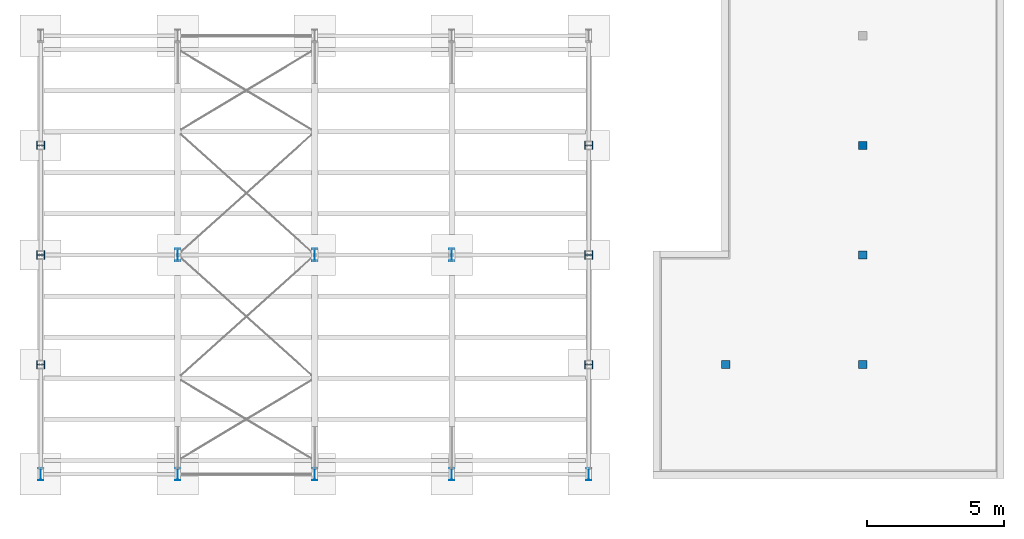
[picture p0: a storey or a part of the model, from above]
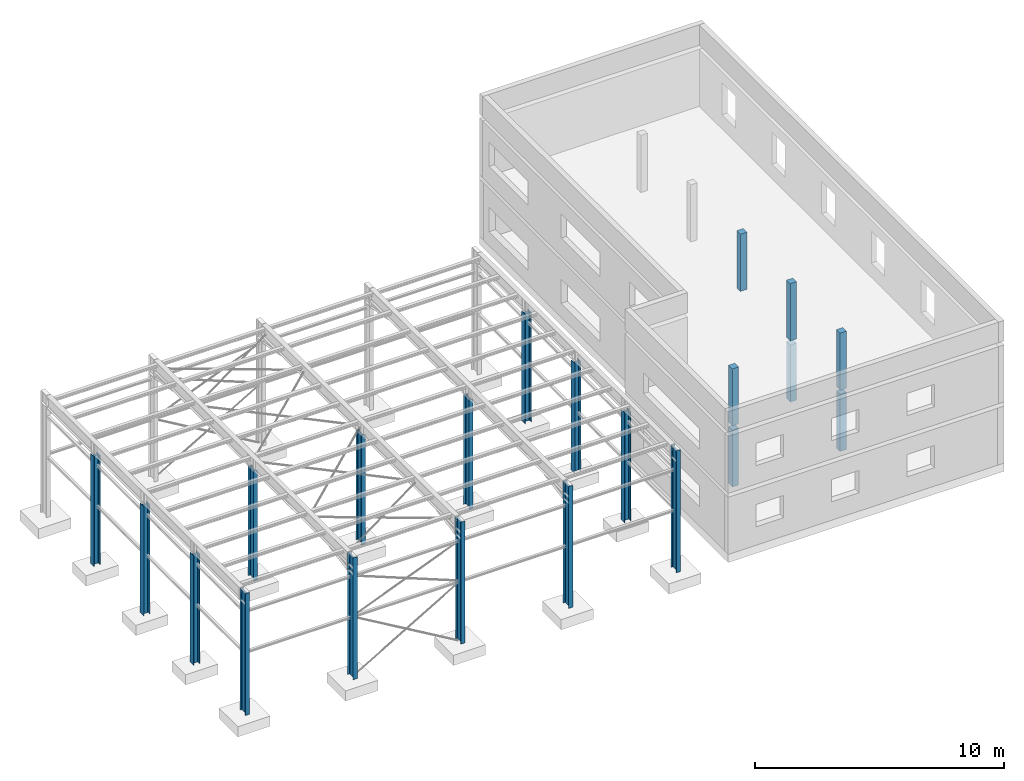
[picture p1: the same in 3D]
Properties of the parts of a building model (IFC4)

# File
Description: ViewDefinition [ReferenceView_V1.2], RevitIdentifiers [VersionGUID: 3cd32a00-ee76-47b4-9a76-ae202fe3ce4a, NumberOfSaves: 37], CoordinateReference [CoordinateBase: Gemeinsam genutzte Koordinaten], ExchangeRequirement [Structural]
File name: IFC_Vorführungsmodell_2.ifc
Time: 2025-12-05T14:43:31+01:00
Written by: ODA SDAI 24.11
Made in: Autodesk Revit 25.0.2.419 (DEU) - IFC 25.0.2.419

# IfcProject, 2018_01
Phase: Projekt Status

# IfcSite, Default
RefLatitude: 48, 8, 15, 359802; RefLongitude: 11, 34, 47, 783432; RefElevation: 0 m
Pset_SiteCommon - Reference: Projektinformationen

# IfcBeam: HEA Träger:HEA 120 (32)
In: Default
Type - PredefinedType: BEAM; Material: Metall - Baustahl S235
Type - Pset_BeamCommon - IsExternal: no; LoadBearing: yes
Pset_BeamCommon - Reference: HEA 120; Slope: 0 deg; Roll: 0 deg
Pset_EnvironmentalImpactIndicators - Reference: HEA 120; sets with these values: 2
Qto_BeamBaseQuantities - CrossSectionArea: 0.00253369 m2
Name (HEA Träger:HEA 120:...) | Span (m) | Length (m) | OuterSurfaceArea (m2) | GrossSurfaceArea (m2) = NetSurfaceArea (m2) | GrossVolume (m3) | NetVolume (m3)
2526143 | 5 | 4.7846 | 3.24108 | 3.24615 | 0.0121227 | 0.0121224
2526321 | 5 | 4.7846 | 3.24108 | 3.24615 | 0.0121227 | 0.0121224
2526471 | 5 | 4.7846 | 3.24108 | 3.24615 | 0.0121227 | 0.0121224
2526497 | 5 | 4.7846 | 3.24108 | 3.24615 | 0.0121227 | 0.0121224
2526596 | 4 | 3.5996 | 2.43836 | 2.44343 | 0.00912027 | 0.00912005
2526643 | 4 | 3.6746 | 2.48917 | 2.49423 | 0.0093103 | 0.00931007
2526716 | 4 | 3.6746 | 2.48917 | 2.49423 | 0.0093103 | 0.00931007
2526732 | 4 | 3.5996 | 2.43836 | 2.44343 | 0.00912027 | 0.00912005
2526779 | 5 | 4.7846 | 3.24108 | 3.24615 | 0.0121227 | 0.0121224
2526805 | 5 | 4.7846 | 3.24108 | 3.24615 | 0.0121227 | 0.0121224
2526849 | 5 | 4.7846 | 3.24108 | 3.24615 | 0.0121227 | 0.0121224
2526873 | 5 | 4.7846 | 3.24108 | 3.24615 | 0.0121227 | 0.0121224
2526911 | 4 | 3.5996 | 2.43836 | 2.44343 | 0.00912027 | 0.00912005
2526929 | 4 | 3.6746 | 2.48917 | 2.49423 | 0.0093103 | 0.00931007
2526979 | 4 | 3.6746 | 2.48917 | 2.49423 | 0.0093103 | 0.00931007
2527025 | 4 | 3.5996 | 2.43836 | 2.44343 | 0.00912027 | 0.00912005
2527203 | 5 | 4.7846 | 3.24108 | 3.24615 | 0.0121227 | 0.0121224
2527204 | 5 | 4.7846 | 3.24108 | 3.24615 | 0.0121227 | 0.0121224
2527205 | 5 | 4.7846 | 3.24108 | 3.24615 | 0.0121227 | 0.0121224
2527206 | 5 | 4.7846 | 3.24108 | 3.24615 | 0.0121227 | 0.0121224
2527208 | 4 | 3.6746 | 2.48917 | 2.49423 | 0.0093103 | 0.00931007
2527209 | 4 | 3.6746 | 2.48917 | 2.49423 | 0.0093103 | 0.00931007
2527210 | 4 | 3.5996 | 2.43836 | 2.44343 | 0.00912027 | 0.00912005
2527211 | 5 | 4.7846 | 3.24108 | 3.24615 | 0.0121227 | 0.0121224
2527212 | 5 | 4.7846 | 3.24108 | 3.24615 | 0.0121227 | 0.0121224
2527213 | 5 | 4.7846 | 3.24108 | 3.24615 | 0.0121227 | 0.0121224
2527214 | 5 | 4.7846 | 3.24108 | 3.24615 | 0.0121227 | 0.0121224
2527215 | 4 | 3.5996 | 2.43836 | 2.44343 | 0.00912027 | 0.00912005
2527216 | 4 | 3.6746 | 2.48917 | 2.49423 | 0.0093103 | 0.00931007
2527217 | 4 | 3.6746 | 2.48917 | 2.49423 | 0.0093103 | 0.00931007
2527218 | 4 | 3.5996 | 2.43836 | 2.44343 | 0.00912027 | 0.00912005
2595123 | 4 | 3.5996 | 2.43836 | 2.44343 | 0.00912027 | 0.00912005

# IfcBeam: HEA Träger:HEA 160 (44)
In: Default
Type - PredefinedType: JOIST; Material: Metall - Baustahl S235
Type - Pset_BeamCommon - IsExternal: no; LoadBearing: yes
Pset_BeamCommon - Span: 5 m; Slope: 0 deg; Roll: 0 deg; Reference: HEA 160
Pset_EnvironmentalImpactIndicators - Reference: HEA 160; sets with these values: 2
Qto_BeamBaseQuantities - Length: 4.7546 m; CrossSectionArea: 0.00387727 m2; OuterSurfaceArea: 4.30885 m2; GrossSurfaceArea: 4.3166 m2; GrossVolume: 0.0184349 m3
Name (HEA Träger:HEA 160:...) | NetSurfaceArea (m2) | NetVolume (m3)
2571911 | 4.3166 | 0.0184344
2572076 | 4.3166 | 0.0184344
2572104 | 4.3166 | 0.0184344
2572118 | 4.3166 | 0.0184344
2572145 | 4.31662 | 0.0184475
2572146 | 4.31662 | 0.0184475
2572147 | 4.31662 | 0.0184475
2572148 | 4.31662 | 0.0184475
2572303 | 4.3166 | 0.0184344
2572304 | 4.3166 | 0.0184344
2572305 | 4.3166 | 0.0184344
2572306 | 4.3166 | 0.0184344
2572316 | 4.3166 | 0.0184344
2572317 | 4.3166 | 0.0184344
2572318 | 4.3166 | 0.0184344
2572319 | 4.3166 | 0.0184344
2572329 | 4.3166 | 0.0184344
2572330 | 4.3166 | 0.0184344
2572331 | 4.3166 | 0.0184344
2572332 | 4.3166 | 0.0184344
2572346 | 4.3166 | 0.0184344
2572347 | 4.3166 | 0.0184344
2572348 | 4.3166 | 0.0184344
2572349 | 4.3166 | 0.0184344
2572419 | 4.3166 | 0.0184344
2572420 | 4.3166 | 0.0184344
2572421 | 4.3166 | 0.0184344
2572422 | 4.3166 | 0.0184344
2572434 | 4.31662 | 0.0184475
2572435 | 4.31662 | 0.0184475
2572436 | 4.31662 | 0.0184475
2572437 | 4.31662 | 0.0184475
2572438 | 4.31662 | 0.0184475
2572439 | 4.31662 | 0.0184475
2572440 | 4.31662 | 0.0184475
2572441 | 4.31662 | 0.0184475
2572442 | 4.31662 | 0.0184475
2572443 | 4.31662 | 0.0184475
2572444 | 4.31662 | 0.0184475
2572445 | 4.31662 | 0.0184475
2572446 | 4.31662 | 0.0184475
2572447 | 4.31662 | 0.0184475
2572448 | 4.31662 | 0.0184475
2572449 | 4.31662 | 0.0184475

# IfcBeam: IPE Träger:IPE 600 (5)
In: Default
Type - PredefinedType: BEAM
Type - Pset_BeamCommon - IsExternal: no; LoadBearing: yes
Description: BP{B4F95C0C-391F-45E2-B43C-3A63B6B80F2F}; Material: Metall - Baustahl S235
Pset_BeamCommon - Slope: 0 deg; Roll: 0 deg; Reference: IPE 600; Span: 16 m
Pset_EnvironmentalImpactIndicators - Reference: IPE 600; sets with these values: 2
Qto_BeamBaseQuantities - NetSurfaceArea: 31.3101 m2; NetVolume: 0.242161 m3
ProfileProperties - SectionFamily: {69B279BA-8278-4C25-AD8E-E1934AC302C2}BP; Section: BP{B4F95C0C-391F-45E2-B43C-3A63B6B80F2F}
Name (IPE Träger:IPE 600:...)
2564772
2564844
2564910
2565005
2564953

# IfcBeam: Rundstahl Träger:RB 20 (14)
In: Default
Type - PredefinedType: BEAM; Material: Metall - Baustahl S235
Type - Pset_BeamCommon - IsExternal: no; LoadBearing: yes
Classification: B10 Uniformat (Uniformat)
Pset_BeamCommon - Roll: 0 deg; Reference: RB 20
Pset_EnvironmentalImpactIndicators - Reference: RB 20; sets with these values: 2
Qto_BeamBaseQuantities - CrossSectionArea: 0.000314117 m2
Name (Rundstahl Träger:RB 20:...) | Span (m) | Slope (deg) | Length (m) | OuterSurfaceArea (m2) | GrossSurfaceArea (m2) = NetSurfaceArea (m2) | GrossVolume (m3) | NetVolume (m3)
2557057 | 5.8019 | 30.4811 | 5.5441 | 0.348346 | 0.348974 | 0.0017415 | 0.00174165
2557153 | 5.8019 | 30.4811 | 5.5441 | 0.348346 | 0.348974 | 0.0017415 | 0.00174165
2557347 | 5.8019 | 30.4811 | 5.5441 | 0.348346 | 0.348974 | 0.0017415 | 0.00174165
2557348 | 5.8019 | 30.4811 | 5.5441 | 0.348346 | 0.348974 | 0.0017415 | 0.00174165
2572734 | 5.8325 | 0 | 5.5383 | 0.347982 | 0.34861 | 0.00173968 | 0.00173983
2572750 | 6.7221 | 0 | 6.3829 | 0.401049 | 0.401678 | 0.00200498 | 0.00200515
2572869 | 6.7224 | 0 | 6.3891 | 0.401439 | 0.402067 | 0.00200693 | 0.0020071
2572887 | 5.8325 | 0 | 5.5383 | 0.347982 | 0.34861 | 0.00173968 | 0.00173983
2572888 | 6.7221 | 0 | 6.3829 | 0.401049 | 0.401678 | 0.00200498 | 0.00200515
2572890 | 6.7224 | 0 | 6.3891 | 0.401439 | 0.402067 | 0.00200693 | 0.0020071
2578470 | 5.3851 | 21.8014 | 5.1471 | 0.323402 | 0.32403 | 0.00161679 | 0.00161693
2578548 | 5.3851 | 21.8014 | 5.1471 | 0.323402 | 0.32403 | 0.00161679 | 0.00161693
2578592 | 5.3851 | 21.8014 | 5.1471 | 0.323402 | 0.32403 | 0.00161679 | 0.00161693
2578593 | 5.3851 | 21.8014 | 5.1471 | 0.323402 | 0.32403 | 0.00161679 | 0.00161693

# IfcBeam: Rundstahl Träger:RB 20 (2)
In: Default
Type - PredefinedType: JOIST; Material: Metall - Baustahl S235
Type - Pset_BeamCommon - IsExternal: no; LoadBearing: yes
Classification: B10 Uniformat (Uniformat)
Pset_BeamCommon - Slope: 0 deg; Roll: 0 deg; Reference: RB 20; Span: 5.8254 m
Pset_EnvironmentalImpactIndicators - Reference: RB 20; sets with these values: 2
Qto_BeamBaseQuantities - Length: 5.5369 m; CrossSectionArea: 0.000314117 m2; OuterSurfaceArea: 0.347894 m2; GrossSurfaceArea: 0.348522 m2; NetSurfaceArea: 0.348522 m2; GrossVolume: 0.00173924 m3; NetVolume: 0.00173939 m3
Name (Rundstahl Träger:RB 20:...)
2572820
2572889

# IfcColumn: HEA Stütze:HEA 300 (6)
In: Default
Type - PredefinedType: COLUMN; Material: Metall - Baustahl S235
Type - Pset_ColumnCommon - IsExternal: no; LoadBearing: yes
Description: BP{29D63AB3-D2AA-4811-B97D-E8A9DB056EDE}
Pset_ColumnCommon - Reference: HEA 300
Pset_EnvironmentalImpactIndicators - Reference: HEA 300; sets with these values: 2
Qto_ColumnBaseQuantities - NetSurfaceArea: 10.3224 m2; NetVolume: 0.0675263 m3
ProfileProperties - SectionFamily: {29D63AB3-D2AA-4811-B97D-E8A9DB056EDE}BP; Section: BP{29D63AB3-D2AA-4811-B97D-E8A9DB056EDE}
Name (HEA Stütze:HEA 300:...)
2521363
2522051
2522128
2522207
2522318
2522393

# IfcColumn: IPE Stütze:IPE 450 (13)
In: Default
Type - PredefinedType: COLUMN; Material: Metall - Baustahl S235
Type - Pset_ColumnCommon - IsExternal: no; LoadBearing: yes
Description: BP{69B279BA-8278-4C25-AD8E-E1934AC302C2}
Pset_ColumnCommon - Reference: IPE 450
Pset_EnvironmentalImpactIndicators - Reference: IPE 450; sets with these values: 2
Qto_ColumnBaseQuantities - NetSurfaceArea: 9.65065 m2; NetVolume: 0.0592979 m3
ProfileProperties - SectionFamily: {69B279BA-8278-4C25-AD8E-E1934AC302C2}BP; Section: BP{69B279BA-8278-4C25-AD8E-E1934AC302C2}
Name (IPE Stütze:IPE 450:...)
2520878
2520965
2521026
2521109
2519903
2520181
2520254
2520431
2520482
2520589
2564533
2564545
2564557

# IfcColumn: STB Stütze - rechteckig:STB 300 x 300 (12)
In: Default
Type - PredefinedType: COLUMN; Material: Ortbeton - bewehrt Verputzt
Type - Pset_ColumnCommon - IsExternal: no; LoadBearing: yes
Qto_ColumnBaseQuantities - Length: 2.8 m; CrossSectionArea: 0.09 m2; OuterSurfaceArea: 3.36 m2; GrossVolume: 0.252 m3; NetVolume: 0.252 m3
Pset_ColumnCommon - Reference: STB 300 x 300
Pset_EnvironmentalImpactIndicators - Reference: STB 300 x 300; sets with these values: 2
Name (STB Stütze - rechteckig:STB 300 x 300:...)
2592392
2592538
2592715
2592792
2592957
2593086
2593540
2593774
2593873
2594064
2594179
2594274

# IfcMechanicalFastener: Bolt (9)
In: Default
NominalDiameter: 0.016 m; NominalLength: 0.065 m

# IfcMechanicalFastener: Bolt#1 (10)
In: Default
NominalDiameter: 0.016 m; NominalLength: 0.06 m

# IfcMechanicalFastener: Bolt#2 (10)
In: Default
NominalDiameter: 0.016 m; NominalLength: 0.06 m

# IfcMechanicalFastener: Bolt#3 (10)
In: Default
NominalDiameter: 0.016 m; NominalLength: 0.06 m

# IfcMechanicalFastener: Bolt#4 (10)
In: Default
NominalDiameter: 0.016 m; NominalLength: 0.06 m

# IfcMechanicalFastener: Bolt#5 (10)
In: Default
NominalDiameter: 0.016 m; NominalLength: 0.06 m

# IfcMechanicalFastener: Bolt#6 (10)
In: Default
NominalDiameter: 0.016 m; NominalLength: 0.06 m

# IfcMechanicalFastener: Bolt#7 (6)
In: Default
NominalDiameter: 0.016 m; NominalLength: 0.06 m

# IfcMechanicalFastener: Bolt#8 (6)
In: Default
NominalDiameter: 0.016 m; NominalLength: 0.06 m

# IfcMember: Haunch (6)
In: Default
Description: BP{B4F95C0C-391F-45E2-B43C-3A63B6B80F2F}
ProfileProperties - SectionFamily: {69B279BA-8278-4C25-AD8E-E1934AC302C2}BP; Section: BP{B4F95C0C-391F-45E2-B43C-3A63B6B80F2F}

# IfcOpeningElement (26)
In: Default
PredefinedType: OPENING
Pset_EnvironmentalImpactIndicators - sets with these values: 2
Name (Basiswand:...) | Depth (m) | Height (m) | Width (m) | Reference
6 x STB 300:2585752 | 0.3 | 1.57123 | 1.06011 | STB 300
3 x STB 300:2585880 | 0.3 | 1.09944 | 1.27939 | STB 300
STB 300:2585969 | 0.3 | 1.0271 | 4.52214 | STB 300
3 x STB 300:2586175 | 0.3 | 1.18312 | 3.12174 | STB 300
6 x STB 250:2586888 | 0.25 | 1.57123 | 1.06011 | STB 250
3 x STB 250:2587039 | 0.25 | 1.09944 | 1.27939 | STB 250
STB 250:2587164 | 0.25 | 1.0271 | 4.52214 | STB 250
3 x STB 250:2588099 | 0.25 | 1.18312 | 3.12174 | STB 250

# IfcPlate: Coverplate (10)
In: Default
Description: -; Material: Dachdeckung - Blechdach 20 m
Pset_PlateCommon - Reference: nicht definiert; IsExternal: no; LoadBearing: no

# IfcPlate: Endplate (19)
In: Default
Description: -; Material: Dachdeckung - Blechdach 15 m
Pset_PlateCommon - Reference: nicht definiert; IsExternal: no; LoadBearing: no

# IfcPlate: Stiffener#1 (9)
In: Default
Description: -; Material: Dachdeckung - Blechdach 14 m
Pset_PlateCommon - Reference: nicht definiert; IsExternal: no; LoadBearing: no

# IfcPlate: Stiffener#14 (6)
In: Default
Description: -; Material: Dachdeckung - Blechdach 15 m
Pset_PlateCommon - Reference: nicht definiert; IsExternal: no; LoadBearing: no

# IfcPlate: Stiffener#2 (29)
In: Default
Description: -
Pset_PlateCommon - Reference: nicht definiert; IsExternal: no; LoadBearing: no
Name | Material
9 x Stiffener#2 | Dachdeckung - Blechdach 14 m
20 x Stiffener#2 | Dachdeckung - Blechdach 15 m

# IfcPlate: Stiffener#3 (15)
In: Default
Description: -
Pset_PlateCommon - Reference: nicht definiert; IsExternal: no; LoadBearing: no
Name | Material
9 x Stiffener#3 | Dachdeckung - Blechdach 14 m
6 x Stiffener#3 | Dachdeckung - Blechdach 15 m

# IfcPlate: Stiffener#4 (9)
In: Default
Description: -; Material: Dachdeckung - Blechdach 14 m
Pset_PlateCommon - Reference: nicht definiert; IsExternal: no; LoadBearing: no

# IfcSlab: Bodenplatte:STB 400, Bodenplatte:STB 400:2591322
In: Default
Type - PredefinedType: BASESLAB; Material: Ortbeton - bewehrt
Type - Pset_SlabCommon - IsExternal: no; ThermalTransmittance: 2.615 kg/K/s3
Pset_EnvironmentalImpactIndicators - Reference: STB 400; sets with these values: 2
Pset_SlabCommon - LoadBearing: yes; PitchAngle: 0 deg; Reference: STB 400
Qto_SlabBaseQuantities - Depth: 0.4 m; Perimeter: 74.217 m; GrossArea: 271.128 m2; NetArea: 271.128 m2; GrossVolume: 108.451 m3; NetVolume: 108.451 m3

# IfcSlab: Einzelfundament:STB 1500 x 1100 x 500 (6)
In: Default
Type - PredefinedType: BASESLAB
Type - Pset_SlabCommon - IsExternal: no
Pset_EnvironmentalImpactIndicators - Reference: STB 1500 x 1100 x 500; sets with these values: 2
Pset_SlabCommon - Reference: STB 1500 x 1100 x 500
Qto_SlabBaseQuantities - Width: 1.1 m; Length: 1.5 m; Depth: 0.5 m; Perimeter: 5.2 m; GrossArea: 1.65 m2; NetArea: 1.65 m2; GrossVolume: 0.825 m3; NetVolume: 0.825 m3
Name (Einzelfundament:STB 1500 x 1100 x 500:...)
2544030
2544391
2544400
2544413
2544422
2544433

# IfcSlab: Einzelfundament:STB 1500 x 1500 x 500 (13)
In: Default
Type - PredefinedType: BASESLAB
Type - Pset_SlabCommon - IsExternal: no
Pset_EnvironmentalImpactIndicators - Reference: STB 1500 x 1500 x 500; sets with these values: 2
Pset_SlabCommon - Reference: STB 1500 x 1500 x 500
Qto_SlabBaseQuantities - Width: 1.5 m; Length: 1.5 m; Depth: 0.5 m; Perimeter: 6 m; GrossArea: 2.25 m2; NetArea: 2.25 m2; GrossVolume: 1.125 m3; NetVolume: 1.125 m3
Name (Einzelfundament:STB 1500 x 1500 x 500:...)
2543343
2543812
2543825
2543834
2543845
2543856
2543869
2543880
2543893
2543906
2564534
2564546
2564558

# IfcSlab: Geschossdecke:STB 200 (2)
In: Default
Type - PredefinedType: FLOOR; Material: Ortbeton - bewehrt
Type - Pset_SlabCommon - IsExternal: no; ThermalTransmittance: 5.23 kg/K/s3
Pset_EnvironmentalImpactIndicators - Reference: STB 200; sets with these values: 2
Pset_SlabCommon - LoadBearing: yes; Reference: STB 200; PitchAngle: 0 deg
Qto_SlabBaseQuantities - Depth: 0.2 m; Perimeter: 74.217 m; GrossArea: 271.128 m2; NetArea: 271.128 m2; GrossVolume: 54.2255 m3; NetVolume: 54.2255 m3
Name (Geschossdecke:STB 200:...)
2588179
2590022

# IfcWall: Basiswand:STB 250 (12)
In: Default
Type - PredefinedType: STANDARD
Type - Pset_WallCommon - IsExternal: yes; ThermalTransmittance: 4.184 kg/K/s3
Material: Ortbeton - bewehrt Verputzt
Qto_WallBaseQuantities - Width: 0.25 m
Pset_EnvironmentalImpactIndicators - Reference: STB 250; sets with these values: 2
Pset_WallCommon - LoadBearing: yes; Reference: STB 250
Name (Basiswand:STB 250:...) | Height (m) | Length (m) | GrossFootprintArea (m2) | GrossVolume (m3) | GrossSideArea (m2) | NetSideArea (m2) | NetVolume (m3) | ExtendToStructure
2586706 | 2.8 | 10.3 | 2.575 | 7.21 | 28.84 | 28.84 | 7.21 | yes
2586888 | 2.8 | 24.0585 | 6.01463 | 16.841 | 67.3638 | 57.3697 | 14.3424 | yes
2587039 | 2.8 | 12.55 | 3.1375 | 8.785 | 35.14 | 30.9202 | 7.73004 | yes
2587164 | 2.8 | 8.05 | 2.0125 | 5.635 | 22.54 | 17.8953 | 4.47382 | yes
2587940 | 2.8 | 2.5 | 0.625 | 1.75 | 7 | 7 | 1.75 | yes
2588099 | 2.8 | 15.7585 | 3.93963 | 11.031 | 44.1238 | 33.0436 | 8.2609 | yes
2589393 | 1 | 10.3 | 2.575 | 2.575 | 10.3 | 10.3 | 2.575 | no
2589535 | 1 | 24.0585 | 6.01463 | 6.01463 | 24.0585 | 24.0585 | 6.01463 | no
2589678 | 1 | 12.55 | 3.1375 | 3.1375 | 12.55 | 12.55 | 3.1375 | no
2589787 | 1 | 8.05 | 2.0125 | 2.0125 | 8.05 | 8.05 | 2.0125 | no
2589839 | 1 | 2.5 | 0.625 | 0.625 | 2.5 | 2.5 | 0.625 | no
2589962 | 1 | 15.7585 | 3.93963 | 3.93963 | 15.7585 | 15.7585 | 3.93963 | no

# IfcWall: Basiswand:STB 300 (6)
In: Default
Type - PredefinedType: STANDARD
Type - Pset_WallCommon - IsExternal: yes; ThermalTransmittance: 3.48667 kg/K/s3
Material: Ortbeton - bewehrt Verputzt
Qto_WallBaseQuantities - Height: 2.8 m; Width: 0.3 m
Pset_EnvironmentalImpactIndicators - Reference: STB 300; sets with these values: 2
Pset_WallCommon - LoadBearing: yes; Reference: STB 300; ExtendToStructure: yes
Name (Basiswand:STB 300:...) | Length (m) | GrossFootprintArea (m2) | GrossVolume (m3) | GrossSideArea (m2) | NetSideArea (m2) | NetVolume (m3)
2585654 | 10.3 | 3.09 | 8.652 | 28.84 | 28.84 | 8.652
2585752 | 24.0085 | 7.20255 | 20.1671 | 67.2238 | 57.2297 | 17.1689
2585880 | 12.5 | 3.75 | 10.5 | 35 | 30.7802 | 9.23405
2585969 | 8 | 2.4 | 6.72 | 22.4 | 17.7553 | 5.32659
2586018 | 2.5 | 0.75 | 2.1 | 7 | 7 | 2.1
2586175 | 15.7085 | 4.71255 | 13.1951 | 43.9838 | 32.9036 | 9.87108
